VERSION 5.7 ;
  NOWIREEXTENSIONATPIN ON ;
  DIVIDERCHAR "/" ;
  BUSBITCHARS "[]" ;
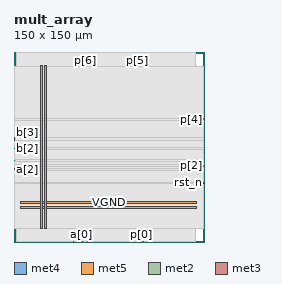
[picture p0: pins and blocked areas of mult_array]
MACRO mult_array
  CLASS BLOCK ;
  FOREIGN mult_array ;
  ORIGIN 0.000 0.000 ;
  SIZE 150.000 BY 150.000 ;
  PIN VGND
    DIRECTION INOUT ;
    USE GROUND ;
    PORT
      LAYER met4 ;
        RECT 24.340 10.640 25.940 138.960 ;
    END
    PORT
      LAYER met5 ;
        RECT 5.520 30.030 144.440 31.630 ;
    END
  END VGND
  PIN VPWR
    DIRECTION INOUT ;
    USE POWER ;
    PORT
      LAYER met4 ;
        RECT 21.040 10.640 22.640 138.960 ;
    END
    PORT
      LAYER met5 ;
        RECT 5.520 26.730 144.440 28.330 ;
    END
  END VPWR
  PIN a[0]
    DIRECTION INPUT ;
    USE SIGNAL ;
    ANTENNAGATEAREA 0.159000 ;
    PORT
      LAYER met2 ;
        RECT 53.450 0.000 53.730 0.280 ;
    END
  END a[0]
  PIN a[1]
    DIRECTION INPUT ;
    USE SIGNAL ;
    ANTENNAGATEAREA 0.159000 ;
    PORT
      LAYER met2 ;
        RECT 59.890 0.000 60.170 0.280 ;
    END
  END a[1]
  PIN a[2]
    DIRECTION INPUT ;
    USE SIGNAL ;
    ANTENNAGATEAREA 0.159000 ;
    PORT
      LAYER met3 ;
        RECT 0.000 57.160 0.600 57.760 ;
    END
  END a[2]
  PIN a[3]
    DIRECTION INPUT ;
    USE SIGNAL ;
    ANTENNAGATEAREA 0.159000 ;
    PORT
      LAYER met3 ;
        RECT 0.000 63.960 0.600 64.560 ;
    END
  END a[3]
  PIN b[0]
    DIRECTION INPUT ;
    USE SIGNAL ;
    ANTENNAGATEAREA 0.159000 ;
    PORT
      LAYER met2 ;
        RECT 58.050 0.000 58.330 0.280 ;
    END
  END b[0]
  PIN b[1]
    DIRECTION INPUT ;
    USE SIGNAL ;
    ANTENNAGATEAREA 0.159000 ;
    PORT
      LAYER met2 ;
        RECT 58.970 0.000 59.250 0.280 ;
    END
  END b[1]
  PIN b[2]
    DIRECTION INPUT ;
    USE SIGNAL ;
    ANTENNAGATEAREA 0.159000 ;
    PORT
      LAYER met3 ;
        RECT 0.000 73.480 0.600 74.080 ;
    END
  END b[2]
  PIN b[3]
    DIRECTION INPUT ;
    USE SIGNAL ;
    ANTENNAGATEAREA 0.159000 ;
    PORT
      LAYER met3 ;
        RECT 0.000 80.280 0.600 80.880 ;
    END
  END b[3]
  PIN clk
    DIRECTION INPUT ;
    USE SIGNAL ;
    ANTENNAGATEAREA 0.852000 ;
    PORT
      LAYER met2 ;
        RECT 47.010 0.000 47.290 0.280 ;
    END
  END clk
  PIN p[0]
    DIRECTION OUTPUT ;
    USE SIGNAL ;
    ANTENNADIFFAREA 0.445500 ;
    PORT
      LAYER met2 ;
        RECT 100.370 0.000 100.650 0.280 ;
    END
  END p[0]
  PIN p[1]
    DIRECTION OUTPUT ;
    USE SIGNAL ;
    ANTENNADIFFAREA 0.445500 ;
    PORT
      LAYER met2 ;
        RECT 102.210 0.000 102.490 0.280 ;
    END
  END p[1]
  PIN p[2]
    DIRECTION OUTPUT ;
    USE SIGNAL ;
    ANTENNADIFFAREA 0.445500 ;
    PORT
      LAYER met3 ;
        RECT 149.400 59.880 150.000 60.480 ;
    END
  END p[2]
  PIN p[3]
    DIRECTION OUTPUT ;
    USE SIGNAL ;
    ANTENNADIFFAREA 0.445500 ;
    PORT
      LAYER met3 ;
        RECT 0.000 81.640 0.600 82.240 ;
    END
  END p[3]
  PIN p[4]
    DIRECTION OUTPUT ;
    USE SIGNAL ;
    ANTENNADIFFAREA 0.445500 ;
    PORT
      LAYER met3 ;
        RECT 149.400 96.600 150.000 97.200 ;
    END
  END p[4]
  PIN p[5]
    DIRECTION OUTPUT ;
    USE SIGNAL ;
    ANTENNADIFFAREA 0.445500 ;
    PORT
      LAYER met2 ;
        RECT 97.610 149.720 97.890 150.000 ;
    END
  END p[5]
  PIN p[6]
    DIRECTION OUTPUT ;
    USE SIGNAL ;
    ANTENNADIFFAREA 0.445500 ;
    PORT
      LAYER met2 ;
        RECT 56.210 149.720 56.490 150.000 ;
    END
  END p[6]
  PIN p[7]
    DIRECTION OUTPUT ;
    USE SIGNAL ;
    ANTENNADIFFAREA 0.445500 ;
    PORT
      LAYER met2 ;
        RECT 58.050 149.720 58.330 150.000 ;
    END
  END p[7]
  PIN rst_n
    DIRECTION INPUT ;
    USE SIGNAL ;
    ANTENNAGATEAREA 0.159000 ;
    PORT
      LAYER met3 ;
        RECT 149.400 46.280 150.000 46.880 ;
    END
  END rst_n
  OBS
      LAYER nwell ;
        RECT 5.330 10.795 144.630 138.910 ;
      LAYER li1 ;
        RECT 5.520 10.795 144.440 138.805 ;
      LAYER met1 ;
        RECT 1.910 10.640 144.440 138.960 ;
      LAYER met2 ;
        RECT 1.930 149.440 55.930 149.720 ;
        RECT 56.770 149.440 57.770 149.720 ;
        RECT 58.610 149.440 97.330 149.720 ;
        RECT 98.170 149.440 142.970 149.720 ;
        RECT 1.930 0.560 142.970 149.440 ;
        RECT 1.930 0.280 46.730 0.560 ;
        RECT 47.570 0.280 53.170 0.560 ;
        RECT 54.010 0.280 57.770 0.560 ;
        RECT 58.610 0.280 58.690 0.560 ;
        RECT 59.530 0.280 59.610 0.560 ;
        RECT 60.450 0.280 100.090 0.560 ;
        RECT 100.930 0.280 101.930 0.560 ;
        RECT 102.770 0.280 142.970 0.560 ;
      LAYER met3 ;
        RECT 0.600 97.600 149.400 138.885 ;
        RECT 0.600 96.200 149.000 97.600 ;
        RECT 0.600 82.640 149.400 96.200 ;
        RECT 1.000 79.880 149.400 82.640 ;
        RECT 0.600 74.480 149.400 79.880 ;
        RECT 1.000 73.080 149.400 74.480 ;
        RECT 0.600 64.960 149.400 73.080 ;
        RECT 1.000 63.560 149.400 64.960 ;
        RECT 0.600 60.880 149.400 63.560 ;
        RECT 0.600 59.480 149.000 60.880 ;
        RECT 0.600 58.160 149.400 59.480 ;
        RECT 1.000 56.760 149.400 58.160 ;
        RECT 0.600 47.280 149.400 56.760 ;
        RECT 0.600 45.880 149.000 47.280 ;
        RECT 0.600 10.715 149.400 45.880 ;
  END
END mult_array
END LIBRARY

